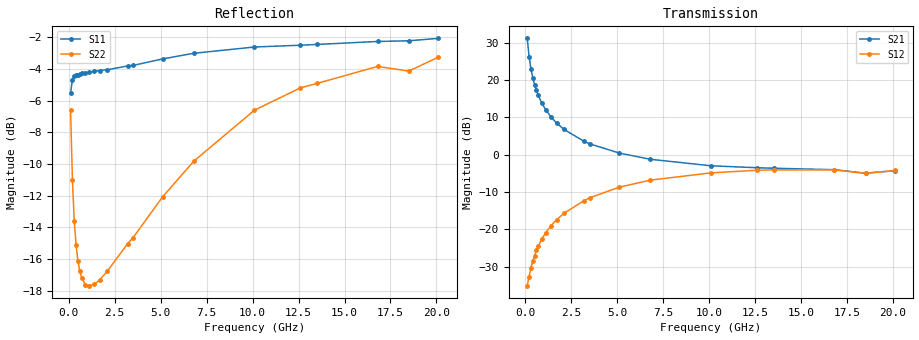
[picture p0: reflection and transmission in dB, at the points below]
!  Infineon Technologies AG
! BFR380L3 , PF131585-7, No.6, Th 09.10.01, soldered on pcb-board, measured with PP GSG850
!  Vce=2.0 V,  Ic=80.0 mA
! Common Emitter S-Parameters:  15. November 2001
#  GHz  S  MA  R  50
! f  S11  S21  S12  S22
! GHz  Mag  Ang  Mag  Ang  Mag  Ang  Mag  Ang
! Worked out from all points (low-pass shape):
!   201 points, 100 MHz to 20.1 GHz, reference 50 ohm
!   highest |S21| = 31.15 dB at 100 MHz (marker M1); lowest = -5.0 dB at 18.5 GHz (marker M2)
!   |S21| within 3 dB of the highest: start of sweep to 161.3 MHz
!   lowest |S11| = -5.5 dB at 100 MHz (marker M3), VSWR 3.25, Z = 18.4 - j20.8 ohm
!   |S11| at or under -10 dB: nowhere
!   |S22| runs from -17.7 to -3.3 dB; largest |S21 - S12| = 36
!   S11 on the Smith chart (normalised r, x): 100 MHz: 0.37, -0.42; 600 MHz: 0.24, -0.01; 3.2 GHz: 0.25, +0.37; 6.8 GHz: 0.30, +0.83; 12.6 GHz: 0.53, +1.58; 20.1 GHz: 1.04, +2.61
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0.1  0.529 -129.6  36.11 122.7  0.01759 56.7  0.4668 -65.6
0.2  0.5838 -154.6  20.57 105.5  0.02332 57.7  0.2818 -90.4
0.3  0.5983 -164.9  14.15 98.2  0.03049 62.1  0.2096 -104.5
0.4  0.6039 -171.1  10.75 93.5  0.03737 65.1  0.1753 -114.8
0.5  0.606 -175.5  8.648 90.0  0.04459 67.8  0.1563 -122.6
0.6  0.6084 -178.8  7.237 87.2  0.05215 69.0  0.1454 -128.7
0.7  0.6113 178.4  6.229 84.7  0.05943 69.9  0.1385 -133.8
0.9  0.6133 173.6  4.871 80.3  0.07462 70.7  0.1317 -141.3
1.1  0.6155 169.7  4.014 76.4  0.08965 70.7  0.1306 -146.7
1.4  0.6207 164.3  3.182 71.1  0.1123 69.9  0.1319 -152.6
1.7  0.624 159.3  2.646 66.1  0.1347 68.6  0.1365 -157.0
2.1  0.6275 153.2  2.177 59.9  0.1642 66.4  0.1452 -161.7
3.2  0.6449 137.6  1.505 44.5  0.243 59.0  0.1771 -173.3
3.5  0.6475 133.6  1.396 40.7  0.2642 56.8  0.1852 -175.4
5.1  0.6788 114.9  1.052 23.4  0.3669 44.6  0.2489 167.9
6.8  0.7073 97.8  0.8671 9.7  0.4562 32.1  0.3228 149.5
10.1  0.7402 73.6  0.7098 -7.7  0.5704 9.5  0.4676 120.4
12.6  0.75 60.8  0.6685 -18.0  0.6184 -6.0  0.55 100.2
13.5  0.7541 56.8  0.6582 -21.8  0.6256 -11.2  0.5681 94.2
16.8  0.7706 45.8  0.6291 -32.8  0.6242 -26.7  0.6427 74.2
18.5  0.7745 44.0  0.5644 -40.2  0.5602 -34.8  0.6214 69.3
20.1  0.7882 37.1  0.6107 -43.4  0.6143 -39.9  0.6875 58.8
